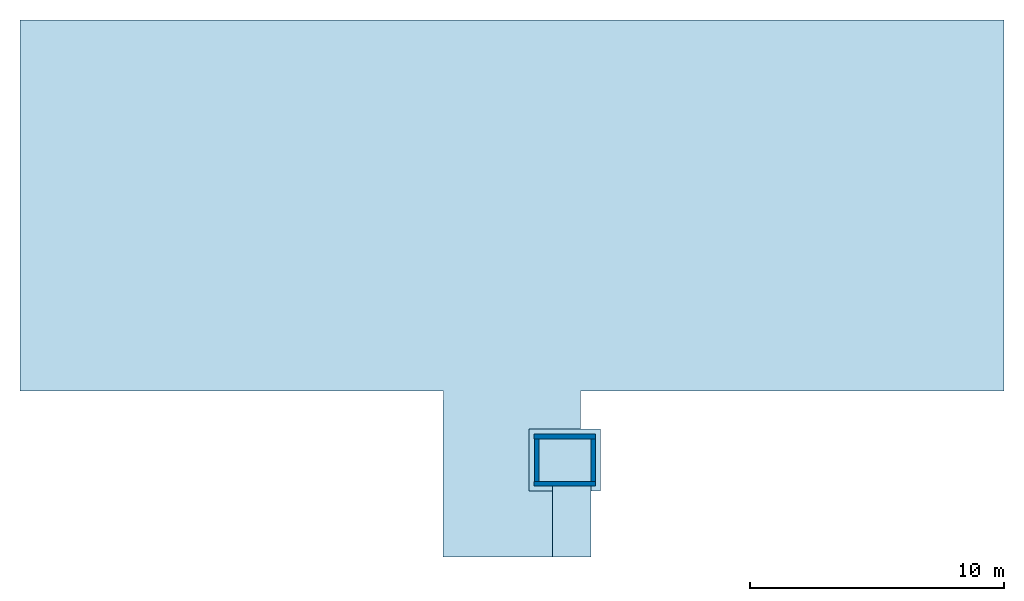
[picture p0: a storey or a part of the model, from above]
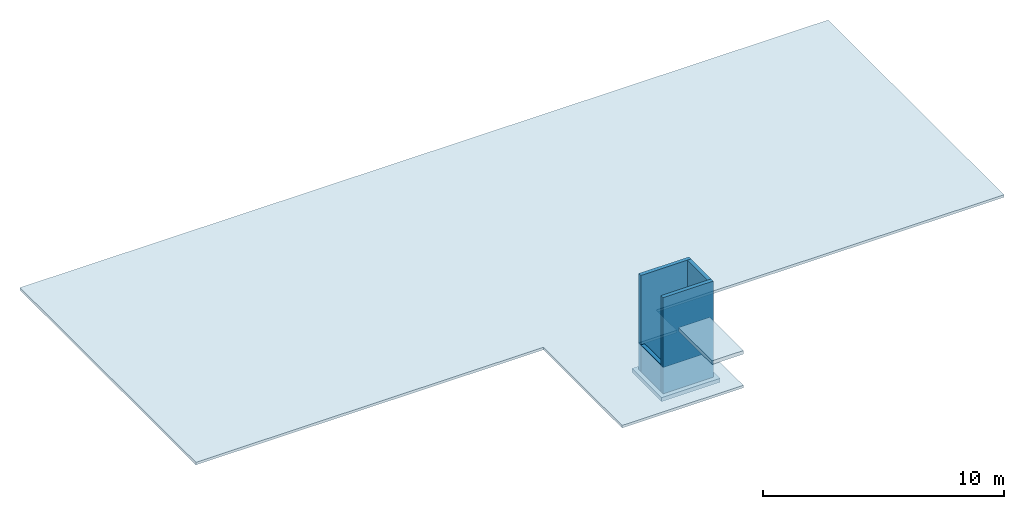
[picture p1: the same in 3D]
Properties of the parts of a building model (IFC2X3)

# File
Description: ViewDefinition [CoordinationView, QuantityTakeOffAddOnView]
File name: Numéro du projet
Time: 2018-01-29T14:30:11
Written by: The EXPRESS Data Manager Version 5.02.0100.07 : 28 Aug 2013
Made in: 20150714_1515(x64) - Exporter 16.0.490.0 - Default UI
Comment: STEP Physical File produced by: The EXPRESS Data Manager Version 5.02.0100.07 : 28 Aug 2013 * Module: EDMstepFileFactory/EDMstandAlone * Creation date: Mon Jan 29 14:30:11 2018 * Host: PC-STEPHANE * Database: C:\Users\STPHAN~1\AppData\Local\Temp\{60ED1AA9-D44B-4950-AAB7-048C5F7BB6E4}\ifc * Database version: 5507 * Database creation date: Mon Jan 29 14:30:02 2018 * Schema: IFC2X3 * Model: DataRepository.ifc * Model creation date: Mon Jan 29 14:30:02 2018 * Header model: DataRepository.ifc_HeaderModel * Header model creation date: Mon Jan 29 14:30:02 2018 * EDMuser: sdai-user * EDMgroup: sdai-group * License ID and type: 5605 : Permanent license. Expiry date: * EDMstepFileFactory options: 020000

# IfcProject, Numéro du projet
LongName: INNOVA PARK; Phase: Etat du projet

# IfcSite, Default
RefLatitude: 48, 51, 57, 604064; RefLongitude: 2, 19, 58, 799800; RefElevation: 0 m
Autre - Adresse du projet: Entrer l'adresse ici; Catégorie: Informations sur le projet; Date de fin du projet: Date de fin; Etat du projet: Etat du projet; Nom du client: Propriétaire; Nom du projet: INNOVA PARK; Numéro de projet: Numéro du projet
Données d'identification - Nom de l'organisation: PROJET BAT2; Nom du bâtiment: BATIMENT 1

# IfcBuilding, BATIMENT 1
LongName: BATIMENT 1
Pset_BuildingCommon - NumberOfStoreys: 5
Autre - Catégorie: Informations sur le projet; Adresse du projet: Entrer l'adresse ici; Date de fin du projet: Date de fin; Etat du projet: Etat du projet; Nom du client: Propriétaire; Nom du projet: INNOVA PARK; Numéro de projet: Numéro du projet
Données d'identification - Nom de l'organisation: PROJET BAT2; Nom du bâtiment: BATIMENT 1

# IfcBuildingStorey (5)
In: BATIMENT 1
Autre - Catégorie: Niveaux; Famille: Niveau: Pointe 8 mm; Famille et type: Niveau: Pointe 8 mm; ID du type: Niveau: Pointe 8 mm; Type: Niveau: Pointe 8 mm; Nom de la famille: Niveau
Cotes - Hauteur de calcul: 0 m
Données d'identification - Structure: no; Etage de bâtiment: yes; Nom du type: Pointe 8 mm
Contraintes - Base de l'élévation: Point de base du projet
Graphismes - Couleur: 0; Epaisseur des lignes: 1; Motif des lignes: Centre; Symbole: M_Marqueur de niveau - Point triangulaire: M_Marqueur de niveau - Point triangulaire; Valeur par défaut du symbole à l'extrémité 1: no; Valeur par défaut du symbole à l'extrémité 2: yes
Name | LongName = Nom | Elevation (m) = Elévation (m)
Fondations | Fondations | -0.7
RdC | RdC | 0
Niveau 1 | Niveau 1 | 3.52
Niveau 2 | Niveau 2 | 7.04
Terrasse brut | Terrasse brut | 10.25

# IfcBeam: Béton - Poutre rectangulaire:BG 0.20 x 0.48 C25/30:421361 (4)
Material: AEC Béton, C25/30
BaseQuantities - GrossVolume: 0.354331 m3
Pset_BeamCommon - LoadBearing: yes; IsExternal: no; Slope: 0 deg; Reference: BG 0.20 x 0.48 C25/30; Span: 1.95 m
Autre - Catégorie: Ossature; Famille: Béton - Poutre rectangulaire: BG 0.20 x 0.48 C25/30; Famille et type: Béton - Poutre rectangulaire: BG 0.20 x 0.48 C25/30; ID du type: Béton - Poutre rectangulaire: BG 0.20 x 0.48 C25/30; Type: Béton - Poutre rectangulaire: BG 0.20 x 0.48 C25/30; Nom de la famille: Béton - Poutre rectangulaire
Contraintes - Décalage du niveau d'arrivée: 0 m; Décalage du niveau de départ: 0 m; Orientation: Normale; Rotation de la section: 0 deg
Cotes - Longueur: 1.95 m; Surface: 0.96 m2; Volume: 0.108 m3; b: 0.2 m; h: 0.48 m
Matériaux et finitions - Matériau structurel: AEC Béton, C25/30
Phase de construction - Phase de création: Nouvelle construction
Position géométrique - Etat de la jonction: Deux jonctions activées; Justification Y: Origine; Justification YZ: Uniforme; Justification Z: Haut; Valeur de décalage Y: 0 m; Valeur de décalage Z: 0 m
Structure - Activer le modèle analytique: yes; Enrobage d'armature - Autres faces: Paramètres de l'enrobage d'armature: Enrobage d'armature 1; Enrobage d'armature - Face inférieure: Paramètres de l'enrobage d'armature: Enrobage d'armature 1; Utilisation structurelle: Longeron; Type d'attachement de début: Elévation d'arrivée; Longueur de coupe: 1.8 m; Forme de coupe: 0
Données d'identification - Nom du type: BG 0.20 x 0.48 C25/30; Numéro OmniClass: 23.25.30.11.14.14; Titre OmniClass: Beams
Name (Béton - Poutre rectangulaire:BG 0.20 x 0.48 C25/30:...) | In | Niveau de référence | Elévation du niveau de référence (m) = Elévation en haut (m) | Plan de construction | Elévation à la base (m)
421407 | Niveau 1 | Niveau: Niveau 1 | 3.52 | Niveau : Niveau 1 | 3.04
421436 | Niveau 1 | Niveau: Niveau 1 | 3.52 | Niveau : Niveau 1 | 3.04
442345 | Niveau 2 | Niveau: Niveau 2 | 7.04 | Niveau : Niveau 2 | 6.56
442348 | Niveau 2 | Niveau: Niveau 2 | 7.04 | Niveau : Niveau 2 | 6.56

# IfcBeam: Béton - Poutre rectangulaire:BG 0.25 x 0.43 C25/30:420141 (6)
In: Niveau 1
Material: AEC Béton, C25/30
Pset_BeamCommon - LoadBearing: yes; IsExternal: no; Slope: 0 deg; Reference: BG 0.25 x 0.43 C25/30
Autre - Catégorie: Ossature; Famille: Béton - Poutre rectangulaire: BG 0.25 x 0.43 C25/30; Famille et type: Béton - Poutre rectangulaire: BG 0.25 x 0.43 C25/30; ID du type: Béton - Poutre rectangulaire: BG 0.25 x 0.43 C25/30; Type: Béton - Poutre rectangulaire: BG 0.25 x 0.43 C25/30; Nom de la famille: Béton - Poutre rectangulaire
Contraintes - Décalage du niveau d'arrivée: 0 m; Décalage du niveau de départ: 0 m; Elévation du niveau de référence: 3.52 m; Niveau de référence: Niveau: Niveau 1; Orientation: Normale; Plan de construction: Niveau : Niveau 1; Rotation de la section: 0 deg
Cotes - Elévation à la base: 3.09 m; Elévation en haut: 3.52 m; b: 0.25 m; h: 0.43 m
Matériaux et finitions - Matériau structurel: AEC Béton, C25/30
Phase de construction - Phase de création: Nouvelle construction
Position géométrique - Etat de la jonction: Deux jonctions activées; Justification Y: Origine; Justification YZ: Uniforme; Justification Z: Haut; Valeur de décalage Y: 0 m; Valeur de décalage Z: 0 m
Structure - Activer le modèle analytique: yes; Enrobage d'armature - Autres faces: Paramètres de l'enrobage d'armature: Enrobage d'armature 1; Enrobage d'armature - Face inférieure: Paramètres de l'enrobage d'armature: Enrobage d'armature 1; Utilisation structurelle: Longeron; Forme de coupe: 0
Données d'identification - Nom du type: BG 0.25 x 0.43 C25/30; Numéro OmniClass: 23.25.30.11.14.14; Titre OmniClass: Beams
Name (Béton - Poutre rectangulaire:BG 0.25 x 0.43 C25/30:...) | Length (m) | CrossSectionArea (m2) | OuterSurfaceArea (m2) | GrossVolume (m3) | Span (m) = Longueur (m) | Surface (m2) | Volume (m3) | Longueur de coupe (m)
420690 | 4.5 | 0.0625 | 4.625 | 2.87073 | 14.8 | 7.1875 | 0.875 | 14.6
420933 | 4.5 | 0.0625 | 4.625 | 2.87073 | 14.8 | 7.1875 | 0.875 | 14.6
420949 | 4.5 | 0.0625 | 4.625 | 2.87073 | 14.8 | 7.1875 | 0.875 | 14.6
420965 | 4.5 | 0.0625 | 4.625 | 2.87073 | 14.8 | 7.1875 | 0.875 | 14.6
421045 |  |  |  | 0.973999 | 5 | 2.4375 | 0.296875 | 4.75 | Structure - Type d'attachement de début: Elévation d'arrivée
421179 |  |  |  | 0.973999 | 5 | 2.4375 | 0.296875 | 4.75 | Structure - Type d'attachement de début: Elévation d'arrivée

# IfcBeam: Béton - Poutre rectangulaire:BG 0.25 x 0.65 C25/30:443021 (6)
In: Niveau 2
Material: AEC Béton, C25/30
Pset_BeamCommon - LoadBearing: yes; IsExternal: no; Slope: 0 deg; Reference: BG 0.25 x 0.65 C25/30
Autre - Catégorie: Ossature; Famille: Béton - Poutre rectangulaire: BG 0.25 x 0.65 C25/30; Famille et type: Béton - Poutre rectangulaire: BG 0.25 x 0.65 C25/30; ID du type: Béton - Poutre rectangulaire: BG 0.25 x 0.65 C25/30; Type: Béton - Poutre rectangulaire: BG 0.25 x 0.65 C25/30; Nom de la famille: Béton - Poutre rectangulaire
Contraintes - Décalage du niveau d'arrivée: 0 m; Décalage du niveau de départ: 0 m; Orientation: Normale; Rotation de la section: 0 deg; Elévation du niveau de référence: 7.04 m; Niveau de référence: Niveau: Niveau 2; Plan de construction: Niveau : Niveau 2
Cotes - Elévation à la base: 6.39 m; Elévation en haut: 7.04 m; b: 0.25 m; h: 0.65 m
Matériaux et finitions - Matériau structurel: AEC Béton, C25/30
Phase de construction - Phase de création: Nouvelle construction
Position géométrique - Etat de la jonction: Deux jonctions activées; Justification Y: Origine; Justification YZ: Uniforme; Justification Z: Haut; Valeur de décalage Y: 0 m; Valeur de décalage Z: 0 m
Structure - Activer le modèle analytique: yes; Enrobage d'armature - Autres faces: Paramètres de l'enrobage d'armature: Enrobage d'armature 1; Enrobage d'armature - Face inférieure: Paramètres de l'enrobage d'armature: Enrobage d'armature 1; Utilisation structurelle: Longeron; Forme de coupe: 0
Données d'identification - Nom du type: BG 0.25 x 0.65 C25/30; Numéro OmniClass: 23.25.30.11.14.14; Titre OmniClass: Beams
Name (Béton - Poutre rectangulaire:BG 0.25 x 0.65 C25/30:...) | Length (m) | CrossSectionArea (m2) | OuterSurfaceArea (m2) | GrossVolume (m3) | Span (m) = Longueur (m) | Surface (m2) | Volume (m3) | Longueur de coupe (m)
442332 | 4.5 | 0.1175 | 6.715 | 5.39698 | 14.8 | 10.4325 | 1.645 | 14.6
442334 | 4.5 | 0.1175 | 6.715 | 5.39698 | 14.8 | 10.4325 | 1.645 | 14.6
442336 | 4.5 | 0.1175 | 6.715 | 5.39698 | 14.8 | 10.4325 | 1.645 | 14.6
442338 | 4.5 | 0.1175 | 6.715 | 5.39698 | 14.8 | 10.4325 | 1.645 | 14.6
442340 |  |  |  | 1.83112 | 5 | 3.5375 | 0.558125 | 4.75 | Structure - Type d'attachement de début: Elévation d'arrivée
442342 |  |  |  | 1.83112 | 5 | 3.5375 | 0.558125 | 4.75 | Structure - Type d'attachement de début: Elévation d'arrivée

# IfcBeam: Béton - Poutre rectangulaire:BG PR 0.20 x 0.39 C25/30:443918 (3)
In: Niveau 2
Material: AEC Béton, C25/30
Pset_BeamCommon - LoadBearing: yes; IsExternal: no; Slope: 0 deg; Reference: BG PR 0.20 x 0.39 C25/30
Autre - Catégorie: Ossature; Famille: Béton - Poutre rectangulaire: BG PR 0.20 x 0.39 C25/30; Famille et type: Béton - Poutre rectangulaire: BG PR 0.20 x 0.39 C25/30; ID du type: Béton - Poutre rectangulaire: BG PR 0.20 x 0.39 C25/30; Type: Béton - Poutre rectangulaire: BG PR 0.20 x 0.39 C25/30; Nom de la famille: Béton - Poutre rectangulaire
Contraintes - Décalage du niveau d'arrivée: 0 m; Décalage du niveau de départ: 0 m; Orientation: Normale; Rotation de la section: 0 deg; Niveau de référence: Niveau: Niveau 2; Elévation du niveau de référence: 7.04 m; Plan de construction: Niveau : Niveau 2
Cotes - Elévation à la base: 6.86 m; Elévation en haut: 7.25 m; b: 0.2 m; h: 0.39 m
Matériaux et finitions - Matériau structurel: AEC Béton, C25/30
Phase de construction - Phase de création: Nouvelle construction
Position géométrique - Etat de la jonction: Deux jonctions activées; Justification Y: Origine; Justification YZ: Uniforme; Justification Z: Haut; Valeur de décalage Y: 0.21 m; Valeur de décalage Z: 0.21 m
Structure - Activer le modèle analytique: yes; Enrobage d'armature - Autres faces: Paramètres de l'enrobage d'armature: Enrobage d'armature 1; Utilisation structurelle: Longeron; Forme de coupe: 0
Données d'identification - Nom du type: BG PR 0.20 x 0.39 C25/30; Numéro OmniClass: 23.25.30.11.14.14; Titre OmniClass: Beams
Name (Béton - Poutre rectangulaire:BG PR 0.20 x 0.39 C25/30:...) | GrossVolume (m3) | Span (m) = Longueur (m) | Surface (m2) | Volume (m3) | Longueur de coupe (m)
444093 | 5.33547 | 38.92 | 15.9385 | 1.62625 | 38.9205 | Structure - Enrobage d'armature - Face inférieure: Paramètres de l'enrobage d'armature: Enrobage d'armature 1
444232 | 2.26949 | 16.66 | 6.8178 | 0.69174 | 16.66 | Structure - Enrobage d'armature - Face supérieure: Paramètres de l'enrobage d'armature: Enrobage d'armature 1
445462 | 2.26811 | 16.66 | 6.81171 | 0.69132 | 16.66

# IfcColumn: BG 0.25 x 0.30 C25/30 (20)
Type - ElementType: BG 0.25 x 0.30 C25/30; PredefinedType: COLUMN; Material: AEC Béton, C25/30
Type - Autre - Catégorie: Poteaux porteurs; Nom de la famille: Béton - Rectangulaire - Poteau
Type - Cotes - b: 0.25 m; h: 0.3 m
Type - Données d'identification - Nom du type: BG 0.25 x 0.30 C25/30
Type - Structure - Forme de coupe: 0
BaseQuantities - Length: 3.34 m; CrossSectionArea: 0.075 m2; OuterSurfaceArea: 3.824 m2
Pset_ColumnCommon - LoadBearing: yes; Reference: BG 0.25 x 0.30 C25/30; IsExternal: no; Slope: 0 deg
Autre - Famille: Béton - Rectangulaire - Poteau: BG 0.25 x 0.30 C25/30; Famille et type: Béton - Rectangulaire - Poteau: BG 0.25 x 0.30 C25/30; ID du type: Béton - Rectangulaire - Poteau: BG 0.25 x 0.30 C25/30; Type: Béton - Rectangulaire - Poteau: BG 0.25 x 0.30 C25/30
Contraintes - Décalage inférieur: 0 m; Décalage supérieur: 0 m; Limite de pièce: yes; Se déplace avec les quadrillages: yes; Style de poteau: Vertical
Matériaux et finitions - Matériau structurel: AEC Béton, C25/30
Phase de construction - Phase de création: Nouvelle construction
Structure - Activer le modèle analytique: yes; Enrobage d'armature - Autres faces: Paramètres de l'enrobage d'armature: Enrobage d'armature 1
Name (Béton - Rectangulaire - Poteau:BG 0.25 x 0.30 C25/30:...) | In | GrossVolume (m3) | Marque d'emplacement du poteau | Niveau = Niveau de base | Niveau supérieur | Longueur (m) | Surface (m2) | Volume (m3)
415848 | Fondations | 0.962106 | B-2 | Niveau: Fondations | Niveau: Niveau 1 | 4.22 | 2.3005 | 0.29325 | Données d'identification - Identifiant: P1; Structure - Enrobage d'armature - Face inférieure: Paramètres de l'enrobage d'armature: Enrobage d'armature 1
416358 | Fondations | 0.962106 | B-3 | Niveau: Fondations | Niveau: Niveau 1 | 4.22 | 2.3005 | 0.29325 | Données d'identification - Identifiant: P2; Structure - Enrobage d'armature - Face inférieure: Paramètres de l'enrobage d'armature: Enrobage d'armature 1
416373 | Fondations | 0.962106 | B-4 | Niveau: Fondations | Niveau: Niveau 1 | 4.22 | 2.3005 | 0.29325 | Structure - Enrobage d'armature - Face inférieure: Paramètres de l'enrobage d'armature: Enrobage d'armature 1
416392 | Fondations | 0.962106 | B-6 | Niveau: Fondations | Niveau: Niveau 1 | 4.22 | 2.3005 | 0.29325 | Structure - Enrobage d'armature - Face inférieure: Paramètres de l'enrobage d'armature: Enrobage d'armature 1
416411 | Fondations | 0.962106 | B-9 | Niveau: Fondations | Niveau: Niveau 1 | 4.22 | 2.3005 | 0.29325 | Structure - Enrobage d'armature - Face inférieure: Paramètres de l'enrobage d'armature: Enrobage d'armature 1
416426 | Fondations | 0.962106 | B-10 | Niveau: Fondations | Niveau: Niveau 1 | 4.22 | 2.3005 | 0.29325 | Structure - Enrobage d'armature - Face inférieure: Paramètres de l'enrobage d'armature: Enrobage d'armature 1
416505 | Fondations | 0.962106 | D-2 | Niveau: Fondations | Niveau: Niveau 1 | 4.22 | 2.3005 | 0.29325 | Structure - Enrobage d'armature - Face inférieure: Paramètres de l'enrobage d'armature: Enrobage d'armature 1
416520 | Fondations | 0.962106 | D-3 | Niveau: Fondations | Niveau: Niveau 1 | 4.22 | 2.3005 | 0.29325 | Structure - Enrobage d'armature - Face inférieure: Paramètres de l'enrobage d'armature: Enrobage d'armature 1
416537 | Fondations | 0.962106 | D-9 | Niveau: Fondations | Niveau: Niveau 1 | 4.22 | 2.3005 | 0.29325 | Structure - Enrobage d'armature - Face inférieure: Paramètres de l'enrobage d'armature: Enrobage d'armature 1
416554 | Fondations | 0.962106 | D-10 | Niveau: Fondations | Niveau: Niveau 1 | 4.22 | 2.3005 | 0.29325 | Structure - Enrobage d'armature - Face inférieure: Paramètres de l'enrobage d'armature: Enrobage d'armature 1
442285 | Niveau 1 | 0.82185 | B-2 | Niveau: Niveau 1 | Niveau: Niveau 2 | 3.52 | 1.912 | 0.2505
442287 | Niveau 1 | 0.82185 | B-3 | Niveau: Niveau 1 | Niveau: Niveau 2 | 3.52 | 1.912 | 0.2505
442289 | Niveau 1 | 0.82185 | B-4 | Niveau: Niveau 1 | Niveau: Niveau 2 | 3.52 | 1.912 | 0.2505
442291 | Niveau 1 | 0.82185 | B-6 | Niveau: Niveau 1 | Niveau: Niveau 2 | 3.52 | 1.912 | 0.2505
442293 | Niveau 1 | 0.82185 | B-9 | Niveau: Niveau 1 | Niveau: Niveau 2 | 3.52 | 1.912 | 0.2505
442295 | Niveau 1 | 0.82185 | B-10 | Niveau: Niveau 1 | Niveau: Niveau 2 | 3.52 | 1.912 | 0.2505
442297 | Niveau 1 | 0.82185 | D-2 | Niveau: Niveau 1 | Niveau: Niveau 2 | 3.52 | 1.912 | 0.2505
442299 | Niveau 1 | 0.82185 | D-3 | Niveau: Niveau 1 | Niveau: Niveau 2 | 3.52 | 1.912 | 0.2505
442301 | Niveau 1 | 0.82185 | D-9 | Niveau: Niveau 1 | Niveau: Niveau 2 | 3.52 | 1.912 | 0.2505
442303 | Niveau 1 | 0.82185 | D-10 | Niveau: Niveau 1 | Niveau: Niveau 2 | 3.52 | 1.912 | 0.2505

# IfcOpeningElement: Opening (93)
BaseQuantities - Depth: 0.2 m
Name | In | Height (m) | Width (m) | Catégorie | Décalage supérieur (m) | Contrainte inférieure | Décalage inférieur (m) | Hauteur non contrainte (m) | Phase de création
14 x Mur de base:BG VOILE BA 0.20 C25/30:410724 | Fondations | 0.92 | 2.1 | Ouverture de mur rectiligne rectangulaire | 0 | Niveau: RdC | 0.1 | 2.1 | Nouvelle construction
5 x Mur de base:BG VOILE BA 0.20 C25/30:416854 | Fondations | 0.92 | 2.1 | Ouverture de mur rectiligne rectangulaire | 0 | Niveau: RdC | 0.1 | 2.1 | Nouvelle construction
Mur de base:BG VOILE BA 0.20 C25/30:416854 | Fondations | 1.07 | 2.16 | Ouverture de mur rectiligne rectangulaire | 0 | Niveau: RdC | 0 | 2.16 | Nouvelle construction
Mur de base:BG VOILE BA 0.20 C25/30:417377 | Fondations | 1.14 | 2.2 | Ouverture de mur rectiligne rectangulaire | 0 | Niveau: RdC | 0.15 | 2.2 | Nouvelle construction
2 x Mur de base:BG VOILE BA 0.20 C25/30:417377 | Fondations | 1.01 | 1.2 | Ouverture de mur rectiligne rectangulaire | 0 | Niveau: RdC | 1 | 1.2 | Nouvelle construction
6 x Mur de base:BG VOILE BA 0.20 C25/30:417552 | Fondations | 0.92 | 2.1 | Ouverture de mur rectiligne rectangulaire | 0 | Niveau: RdC | 0.1 | 2.1 | Nouvelle construction
Mur de base:BG VOILE BA 0.20 C25/30:418211 | Fondations | 1.14 | 2.2 | Ouverture de mur rectiligne rectangulaire | 0 | Niveau: RdC | 0.15 | 2.2 | Nouvelle construction
2 x Mur de base:BG VOILE BA 0.20 C25/30:418211 | Fondations | 1.01 | 1.2 | Ouverture de mur rectiligne rectangulaire | 0 | Niveau: RdC | 1 | 1.2 | Nouvelle construction
14 x Mur de base:BG VOILE BA 0.20 C25/30:442282 | Niveau 1 | 0.92 | 2.08 | Ouverture de mur rectiligne rectangulaire | 0 | Niveau: Niveau 1 | 0.12 | 2.08 | Nouvelle construction
6 x Mur de base:BG VOILE BA 0.20 C25/30:442309 | Niveau 1 | 0.92 | 2.08 | Ouverture de mur rectiligne rectangulaire | 0 | Niveau: Niveau 1 | 0.12 | 2.08 | Nouvelle construction
Mur de base:BG VOILE BA 0.20 C25/30:442313 | Niveau 1 | 1.05 | 2.2 | Ouverture de mur rectiligne rectangulaire | 0 | Niveau: Niveau 1 | 0 | 2.2 | Nouvelle construction
2 x Mur de base:BG VOILE BA 0.20 C25/30:442313 | Niveau 1 | 0.92 | 1.2 | Ouverture de mur rectiligne rectangulaire | 0 | Niveau: Niveau 1 | 1 | 1.2 | Nouvelle construction
6 x Mur de base:BG VOILE BA 0.20 C25/30:442315 | Niveau 1 | 0.92 | 2.08 | Ouverture de mur rectiligne rectangulaire | 0 | Niveau: Niveau 1 | 0.12 | 2.08 | Nouvelle construction
Mur de base:BG VOILE BA 0.20 C25/30:442319 | Niveau 1 | 1.05 | 2.2 | Ouverture de mur rectiligne rectangulaire | 0 | Niveau: Niveau 1 | 0 | 2.2 | Nouvelle construction
2 x Mur de base:BG VOILE BA 0.20 C25/30:442319 | Niveau 1 | 0.92 | 1.2 | Ouverture de mur rectiligne rectangulaire | 0 | Niveau: Niveau 1 | 1 | 1.2 | Nouvelle construction
14 x Mur de base:BG VOILE BA 0.20 C25/30:447258 | Niveau 2 | 0.92 | 2.1 | Ouverture de mur rectiligne rectangulaire | 0 | Niveau: Niveau 2 | 0.3 | 2.1 | Nouvelle construction
Mur de base:BG VOILE BA 0.20 C25/30:448893 | Niveau 2 | 1.05 | 2.2 | Ouverture de mur rectiligne rectangulaire | 0 | Niveau: Niveau 2 | 0 | 2.2 | Nouvelle construction
Mur de base:BG VOILE BA 0.20 C25/30:449741 | Niveau 2 | 1.05 | 2.2 | Ouverture de mur rectiligne rectangulaire | 0 | Niveau: Niveau 2 | 0 | 2.2 | Nouvelle construction
6 x Mur de base:BG VOILE BA 0.20 C25/30:449856 | Niveau 2 | 0.92 | 2.1 | Ouverture de mur rectiligne rectangulaire | 0 | Niveau: Niveau 2 | 0.3 | 2.1 | Nouvelle construction
6 x Mur de base:BG VOILE BA 0.20 C25/30:450434 | Niveau 2 | 0.92 | 2.1 | Ouverture de mur rectiligne rectangulaire | -0.81 | Niveau: Niveau 2 | 0.3 | 2.1 | Nouvelle construction | Contraintes - Contrainte supérieure: Niveau: Terrasse brut
 | Terrasse brut | 2.02 | 1.02

# IfcSlab: M_Base-Rectangulaire:BG SI 0.80 x 0.80 x 0.25 C25/30, M_Base-Rectangulaire:BG SI 0.80 x 0.80 x 0.25 C25/30:431764
In: Fondations
PredefinedType: FLOOR; Material: AEC Béton, C25/30
Pset_SlabCommon - LoadBearing: yes; IsExternal: no; Reference: BG SI 0.80 x 0.80 x 0.25 C25/30
Autre - Catégorie: Fondations; Famille: M_Base-Rectangulaire: BG SI 0.80 x 0.80 x 0.25 C25/30; Famille et type: M_Base-Rectangulaire: BG SI 0.80 x 0.80 x 0.25 C25/30; ID du type: M_Base-Rectangulaire: BG SI 0.80 x 0.80 x 0.25 C25/30; Type: M_Base-Rectangulaire: BG SI 0.80 x 0.80 x 0.25 C25/30; Nom de la famille: M_Base-Rectangulaire
Contraintes - Niveau: Niveau: Fondations; Se déplace avec les quadrillages: yes; Décalage: 0 m; Hôte: Niveau : Fondations
Cotes - Elévation à la base: -0.95 m; Elévation en haut: -0.7 m; Largeur: 0.8 m; Longueur: 0.8 m; Surface: 0.64 m2; Volume: 0.16 m3; Epaisseur: 0.25 m
Matériaux et finitions - Matériau structurel: AEC Béton, C25/30
Phase de construction - Phase de création: Nouvelle construction
Structure - Activer le modèle analytique: yes; Enrobage d'armature - Autres faces: Paramètres de l'enrobage d'armature: Enrobage d'armature 1; Enrobage d'armature - Face inférieure: Paramètres de l'enrobage d'armature: Enrobage d'armature 1; Enrobage d'armature - Face supérieure: Paramètres de l'enrobage d'armature: Enrobage d'armature 1
Données d'identification - Nom du type: BG SI 0.80 x 0.80 x 0.25 C25/30

# IfcSlab: M_Base-Rectangulaire:BG SI 1.00 x 1.00 x 0.25 C25/30, M_Base-Rectangulaire:BG SI 1.00 x 1.00 x 0.25 C25/30:432122
In: Fondations
PredefinedType: FLOOR; Material: AEC Béton, C25/30
Pset_SlabCommon - LoadBearing: yes; IsExternal: no; Reference: BG SI 1.00 x 1.00 x 0.25 C25/30
Autre - Catégorie: Fondations; Famille: M_Base-Rectangulaire: BG SI 1.00 x 1.00 x 0.25 C25/30; Famille et type: M_Base-Rectangulaire: BG SI 1.00 x 1.00 x 0.25 C25/30; ID du type: M_Base-Rectangulaire: BG SI 1.00 x 1.00 x 0.25 C25/30; Type: M_Base-Rectangulaire: BG SI 1.00 x 1.00 x 0.25 C25/30; Nom de la famille: M_Base-Rectangulaire
Contraintes - Se déplace avec les quadrillages: yes; Décalage: 0 m; Niveau: Niveau: Fondations; Hôte: Niveau : Fondations
Cotes - Elévation à la base: -0.95 m; Elévation en haut: -0.7 m; Largeur: 1 m; Longueur: 1 m; Surface: 1 m2; Volume: 0.25 m3; Epaisseur: 0.25 m
Matériaux et finitions - Matériau structurel: AEC Béton, C25/30
Phase de construction - Phase de création: Nouvelle construction
Structure - Activer le modèle analytique: yes; Enrobage d'armature - Autres faces: Paramètres de l'enrobage d'armature: Enrobage d'armature 1; Enrobage d'armature - Face inférieure: Paramètres de l'enrobage d'armature: Enrobage d'armature 1; Enrobage d'armature - Face supérieure: Paramètres de l'enrobage d'armature: Enrobage d'armature 1
Données d'identification - Nom du type: BG SI 1.00 x 1.00 x 0.25 C25/30

# IfcSlab: M_Base-Rectangulaire:BG SI 1.10 x 1.10 x 0.30 C25/30 (3)
In: Fondations
PredefinedType: FLOOR; Material: AEC Béton, C25/30
Pset_SlabCommon - LoadBearing: yes; IsExternal: no; Reference: BG SI 1.10 x 1.10 x 0.30 C25/30
Autre - Catégorie: Fondations; Famille: M_Base-Rectangulaire: BG SI 1.10 x 1.10 x 0.30 C25/30; Famille et type: M_Base-Rectangulaire: BG SI 1.10 x 1.10 x 0.30 C25/30; ID du type: M_Base-Rectangulaire: BG SI 1.10 x 1.10 x 0.30 C25/30; Type: M_Base-Rectangulaire: BG SI 1.10 x 1.10 x 0.30 C25/30; Nom de la famille: M_Base-Rectangulaire
Contraintes - Niveau: Niveau: Fondations; Se déplace avec les quadrillages: yes; Décalage: 0 m; Hôte: Niveau : Fondations
Cotes - Elévation à la base: -1 m; Elévation en haut: -0.7 m; Largeur: 1.1 m; Longueur: 1.1 m; Surface: 1.21 m2; Volume: 0.363 m3; Epaisseur: 0.3 m
Matériaux et finitions - Matériau structurel: AEC Béton, C25/30
Phase de construction - Phase de création: Nouvelle construction
Structure - Activer le modèle analytique: yes; Enrobage d'armature - Autres faces: Paramètres de l'enrobage d'armature: Enrobage d'armature 1; Enrobage d'armature - Face inférieure: Paramètres de l'enrobage d'armature: Enrobage d'armature 1; Enrobage d'armature - Face supérieure: Paramètres de l'enrobage d'armature: Enrobage d'armature 1
Données d'identification - Nom du type: BG SI 1.10 x 1.10 x 0.30 C25/30
Name (M_Base-Rectangulaire:BG SI 1.10 x 1.10 x 0.30 C25/30:...)
433193
433422
433663

# IfcSlab: M_Base-Rectangulaire:BG SI 1.20x 2.40 x 0.35 C25/30 (2)
In: Fondations
PredefinedType: FLOOR; Material: AEC Béton, C25/30
Pset_SlabCommon - LoadBearing: yes; IsExternal: no; Reference: BG SI 1.20x 2.40 x 0.35 C25/30
Autre - Catégorie: Fondations; Famille: M_Base-Rectangulaire: BG SI 1.20x 2.40 x 0.35 C25/30; Famille et type: M_Base-Rectangulaire: BG SI 1.20x 2.40 x 0.35 C25/30; ID du type: M_Base-Rectangulaire: BG SI 1.20x 2.40 x 0.35 C25/30; Type: M_Base-Rectangulaire: BG SI 1.20x 2.40 x 0.35 C25/30; Nom de la famille: M_Base-Rectangulaire
Contraintes - Niveau: Niveau: Fondations; Se déplace avec les quadrillages: yes; Décalage: 0 m; Hôte: Niveau : Fondations
Cotes - Elévation à la base: -1.05 m; Elévation en haut: -0.7 m; Largeur: 1.2 m; Longueur: 2.4 m; Surface: 2.88 m2; Volume: 1.008 m3; Epaisseur: 0.35 m
Matériaux et finitions - Matériau structurel: AEC Béton, C25/30
Phase de construction - Phase de création: Nouvelle construction
Structure - Activer le modèle analytique: yes; Enrobage d'armature - Autres faces: Paramètres de l'enrobage d'armature: Enrobage d'armature 1; Enrobage d'armature - Face inférieure: Paramètres de l'enrobage d'armature: Enrobage d'armature 1; Enrobage d'armature - Face supérieure: Paramètres de l'enrobage d'armature: Enrobage d'armature 1
Données d'identification - Nom du type: BG SI 1.20x 2.40 x 0.35 C25/30
Name (M_Base-Rectangulaire:BG SI 1.20x 2.40 x 0.35 C25/30:...)
431236
431718

# IfcSlab: M_Base-Rectangulaire:BG SI 1.30 x 1.30 x 0.35 C25/30, M_Base-Rectangulaire:BG SI 1.30 x 1.30 x 0.35 C25/30:432809
In: Fondations
PredefinedType: FLOOR; Material: AEC Béton, C25/30
Pset_SlabCommon - LoadBearing: yes; IsExternal: no; Reference: BG SI 1.30 x 1.30 x 0.35 C25/30
Autre - Catégorie: Fondations; Famille: M_Base-Rectangulaire: BG SI 1.30 x 1.30 x 0.35 C25/30; Famille et type: M_Base-Rectangulaire: BG SI 1.30 x 1.30 x 0.35 C25/30; ID du type: M_Base-Rectangulaire: BG SI 1.30 x 1.30 x 0.35 C25/30; Type: M_Base-Rectangulaire: BG SI 1.30 x 1.30 x 0.35 C25/30; Nom de la famille: M_Base-Rectangulaire
Contraintes - Niveau: Niveau: Fondations; Se déplace avec les quadrillages: yes; Décalage: 0 m; Hôte: Niveau : Fondations
Cotes - Elévation à la base: -1.05 m; Elévation en haut: -0.7 m; Largeur: 1.3 m; Longueur: 1.3 m; Surface: 1.69 m2; Volume: 0.5915 m3; Epaisseur: 0.35 m
Matériaux et finitions - Matériau structurel: AEC Béton, C25/30
Phase de construction - Phase de création: Nouvelle construction
Structure - Activer le modèle analytique: yes; Enrobage d'armature - Autres faces: Paramètres de l'enrobage d'armature: Enrobage d'armature 1; Enrobage d'armature - Face inférieure: Paramètres de l'enrobage d'armature: Enrobage d'armature 1; Enrobage d'armature - Face supérieure: Paramètres de l'enrobage d'armature: Enrobage d'armature 1
Données d'identification - Nom du type: BG SI 1.30 x 1.30 x 0.35 C25/30

# IfcSlab: M_Base-Rectangulaire:BG SI 1.40 x 1.40 x 0.35 C25/30 (6)
In: Fondations
PredefinedType: FLOOR; Material: AEC Béton, C25/30
Pset_SlabCommon - LoadBearing: yes; IsExternal: no; Reference: BG SI 1.40 x 1.40 x 0.35 C25/30
Autre - Catégorie: Fondations; Famille: M_Base-Rectangulaire: BG SI 1.40 x 1.40 x 0.35 C25/30; Famille et type: M_Base-Rectangulaire: BG SI 1.40 x 1.40 x 0.35 C25/30; ID du type: M_Base-Rectangulaire: BG SI 1.40 x 1.40 x 0.35 C25/30; Type: M_Base-Rectangulaire: BG SI 1.40 x 1.40 x 0.35 C25/30; Nom de la famille: M_Base-Rectangulaire
Contraintes - Niveau: Niveau: Fondations; Se déplace avec les quadrillages: yes; Décalage: 0 m; Hôte: Niveau : Fondations
Cotes - Elévation à la base: -1.05 m; Elévation en haut: -0.7 m; Largeur: 1.4 m; Longueur: 1.4 m; Surface: 1.96 m2; Volume: 0.686 m3; Epaisseur: 0.35 m
Matériaux et finitions - Matériau structurel: AEC Béton, C25/30
Phase de construction - Phase de création: Nouvelle construction
Structure - Activer le modèle analytique: yes; Enrobage d'armature - Autres faces: Paramètres de l'enrobage d'armature: Enrobage d'armature 1; Enrobage d'armature - Face inférieure: Paramètres de l'enrobage d'armature: Enrobage d'armature 1; Enrobage d'armature - Face supérieure: Paramètres de l'enrobage d'armature: Enrobage d'armature 1
Données d'identification - Nom du type: BG SI 1.40 x 1.40 x 0.35 C25/30
Name (M_Base-Rectangulaire:BG SI 1.40 x 1.40 x 0.35 C25/30:...)
427728 | Données d'identification - Identifiant: S5
427982
427991
427998
430670
430679

# IfcSlab: M_Base-Rectangulaire:BG SI 1.50x 1.50 x 0.40 C25/30 (3)
In: Fondations
PredefinedType: FLOOR; Material: AEC Béton, C25/30
Pset_SlabCommon - LoadBearing: yes; IsExternal: no; Reference: BG SI 1.50x 1.50 x 0.40 C25/30
Autre - Catégorie: Fondations; Famille: M_Base-Rectangulaire: BG SI 1.50x 1.50 x 0.40 C25/30; Famille et type: M_Base-Rectangulaire: BG SI 1.50x 1.50 x 0.40 C25/30; ID du type: M_Base-Rectangulaire: BG SI 1.50x 1.50 x 0.40 C25/30; Type: M_Base-Rectangulaire: BG SI 1.50x 1.50 x 0.40 C25/30; Nom de la famille: M_Base-Rectangulaire
Contraintes - Se déplace avec les quadrillages: yes; Décalage: 0 m; Niveau: Niveau: Fondations; Hôte: Niveau : Fondations
Cotes - Elévation à la base: -1.1 m; Elévation en haut: -0.7 m; Largeur: 1.5 m; Longueur: 1.5 m; Surface: 2.25 m2; Volume: 0.9 m3; Epaisseur: 0.4 m
Matériaux et finitions - Matériau structurel: AEC Béton, C25/30
Phase de construction - Phase de création: Nouvelle construction
Structure - Activer le modèle analytique: yes; Enrobage d'armature - Autres faces: Paramètres de l'enrobage d'armature: Enrobage d'armature 1; Enrobage d'armature - Face inférieure: Paramètres de l'enrobage d'armature: Enrobage d'armature 1; Enrobage d'armature - Face supérieure: Paramètres de l'enrobage d'armature: Enrobage d'armature 1
Données d'identification - Nom du type: BG SI 1.50x 1.50 x 0.40 C25/30
Name (M_Base-Rectangulaire:BG SI 1.50x 1.50 x 0.40 C25/30:...)
430786
430795
432445

# IfcSlab: M_Base-Rectangulaire:BG SI 1.70 x 1.70 x 0.45 C25/30 (18)
In: Fondations
PredefinedType: FLOOR; Material: AEC Béton, C25/30
Pset_SlabCommon - LoadBearing: yes; IsExternal: no; Reference: BG SI 1.70 x 1.70 x 0.45 C25/30
Autre - Catégorie: Fondations; Famille: M_Base-Rectangulaire: BG SI 1.70 x 1.70 x 0.45 C25/30; Famille et type: M_Base-Rectangulaire: BG SI 1.70 x 1.70 x 0.45 C25/30; ID du type: M_Base-Rectangulaire: BG SI 1.70 x 1.70 x 0.45 C25/30; Type: M_Base-Rectangulaire: BG SI 1.70 x 1.70 x 0.45 C25/30; Nom de la famille: M_Base-Rectangulaire
Contraintes - Se déplace avec les quadrillages: yes; Décalage: 0 m; Niveau: Niveau: Fondations; Hôte: Niveau : Fondations
Cotes - Elévation à la base: -1.15 m; Elévation en haut: -0.7 m; Largeur: 1.7 m; Longueur: 1.7 m; Surface: 2.89 m2; Volume: 1.3005 m3; Epaisseur: 0.45 m
Matériaux et finitions - Matériau structurel: AEC Béton, C25/30
Phase de construction - Phase de création: Nouvelle construction
Structure - Activer le modèle analytique: yes; Enrobage d'armature - Autres faces: Paramètres de l'enrobage d'armature: Enrobage d'armature 1; Enrobage d'armature - Face inférieure: Paramètres de l'enrobage d'armature: Enrobage d'armature 1; Enrobage d'armature - Face supérieure: Paramètres de l'enrobage d'armature: Enrobage d'armature 1
Données d'identification - Nom du type: BG SI 1.70 x 1.70 x 0.45 C25/30
Name (M_Base-Rectangulaire:BG SI 1.70 x 1.70 x 0.45 C25/30:...)
428045
428682
428691
428706
428715
428724
428818
428997
429438
429589
429854
429863
429876
429883
429953
429955
429957
429959

# IfcSlab: M_Base-Rectangulaire:BG SI 1.80 x 1.80 x 0.45 C25/30, M_Base-Rectangulaire:BG SI 1.80 x 1.80 x 0.45 C25/30:432512
In: Fondations
PredefinedType: FLOOR; Material: AEC Béton, C25/30
Pset_SlabCommon - LoadBearing: yes; IsExternal: no; Reference: BG SI 1.80 x 1.80 x 0.45 C25/30
Autre - Catégorie: Fondations; Famille: M_Base-Rectangulaire: BG SI 1.80 x 1.80 x 0.45 C25/30; Famille et type: M_Base-Rectangulaire: BG SI 1.80 x 1.80 x 0.45 C25/30; ID du type: M_Base-Rectangulaire: BG SI 1.80 x 1.80 x 0.45 C25/30; Type: M_Base-Rectangulaire: BG SI 1.80 x 1.80 x 0.45 C25/30; Nom de la famille: M_Base-Rectangulaire
Contraintes - Niveau: Niveau: Fondations; Se déplace avec les quadrillages: yes; Décalage: 0 m; Hôte: Niveau : Fondations
Cotes - Elévation à la base: -1.15 m; Elévation en haut: -0.7 m; Largeur: 1.8 m; Longueur: 1.8 m; Surface: 3.24 m2; Volume: 1.458 m3; Epaisseur: 0.45 m
Matériaux et finitions - Matériau structurel: AEC Béton, C25/30
Phase de construction - Phase de création: Nouvelle construction
Structure - Activer le modèle analytique: yes; Enrobage d'armature - Autres faces: Paramètres de l'enrobage d'armature: Enrobage d'armature 1; Enrobage d'armature - Face inférieure: Paramètres de l'enrobage d'armature: Enrobage d'armature 1; Enrobage d'armature - Face supérieure: Paramètres de l'enrobage d'armature: Enrobage d'armature 1
Données d'identification - Nom du type: BG SI 1.80 x 1.80 x 0.45 C25/30

# IfcSlab: M_Base-Rectangulaire:BG SI 1.90x 0.50 x 0.25 C25/30, M_Base-Rectangulaire:BG SI 1.90x 0.50 x 0.25 C25/30:433990
In: Fondations
PredefinedType: FLOOR; Material: AEC Béton, C25/30
Pset_SlabCommon - LoadBearing: yes; IsExternal: no; Reference: BG SI 1.90x 0.50 x 0.25 C25/30
Autre - Catégorie: Fondations; Famille: M_Base-Rectangulaire: BG SI 1.90x 0.50 x 0.25 C25/30; Famille et type: M_Base-Rectangulaire: BG SI 1.90x 0.50 x 0.25 C25/30; ID du type: M_Base-Rectangulaire: BG SI 1.90x 0.50 x 0.25 C25/30; Type: M_Base-Rectangulaire: BG SI 1.90x 0.50 x 0.25 C25/30; Nom de la famille: M_Base-Rectangulaire
Contraintes - Se déplace avec les quadrillages: yes; Décalage: 0 m; Niveau: Niveau: Fondations; Hôte: Niveau : Fondations
Cotes - Elévation à la base: -0.95 m; Elévation en haut: -0.7 m; Largeur: 1.9 m; Longueur: 0.5 m; Surface: 0.95 m2; Volume: 0.2375 m3; Epaisseur: 0.25 m
Matériaux et finitions - Matériau structurel: AEC Béton, C25/30
Phase de construction - Phase de création: Nouvelle construction
Structure - Activer le modèle analytique: yes; Enrobage d'armature - Autres faces: Paramètres de l'enrobage d'armature: Enrobage d'armature 1; Enrobage d'armature - Face inférieure: Paramètres de l'enrobage d'armature: Enrobage d'armature 1; Enrobage d'armature - Face supérieure: Paramètres de l'enrobage d'armature: Enrobage d'armature 1
Données d'identification - Nom du type: BG SI 1.90x 0.50 x 0.25 C25/30

# IfcSlab: Radier:BG 2.80 x 2.45 x 0.20, Radier:BG 2.80 x 2.45 x 0.20:434525
In: RdC
PredefinedType: BASESLAB; Material: BETON C25/30 0.2 m
Pset_SlabCommon - LoadBearing: yes; IsExternal: no; PitchAngle: 0 deg; Reference: BG 2.80 x 2.45 x 0.20
BaseQuantities - GrossArea: 6.86 m2; GrossVolume: 1.372 m3; Perimeter: 10.5 m; Width: 0.2 m
Autre - Catégorie: Fondations; Famille: Radier: BG 2.80 x 2.45 x 0.20; Famille et type: Radier: BG 2.80 x 2.45 x 0.20; ID du type: Radier: BG 2.80 x 2.45 x 0.20; Type: Radier: BG 2.80 x 2.45 x 0.20; Nom de la famille: Radier
Contraintes - Lié au volume: no; Niveau: Niveau: RdC; Décalage par rapport au niveau: -1.35 m
Cotes - Elévation à la base: -1.55 m; Elévation au niveau du noyau inférieur: -1.55 m; Elévation au niveau du noyau supérieur: -1.35 m; Elévation en haut: -1.35 m; Epaisseur: 0.2 m; Largeur: 2.8 m; Longueur: 2.45 m; Périmètre: 10.5 m; Surface: 6.86 m2; Volume: 1.372 m3
Phase de construction - Phase de création: Nouvelle construction
Structure - Activer le modèle analytique: yes; Enrobage d'armature - Autres faces: Paramètres de l'enrobage d'armature: Enrobage d'armature 1; Structure: yes; Enrobage d'armature - Face inférieure: Paramètres de l'enrobage d'armature: Enrobage d'armature 1; Enrobage d'armature - Face supérieure: Paramètres de l'enrobage d'armature: Enrobage d'armature 1
Construction - Epaisseur par défaut: 0.2 m
Données d'identification - Nom du type: BG 2.80 x 2.45 x 0.20
Graphismes - Couleur vue détail faible: 0
Matériaux et finitions - Matériau structurel: BETON C25/30
Propriétés analytiques - Rugosité: 3; Coefficient d'absorbance: 0.7

# IfcSlab: Sol:BG DALLAGE BA 0.13 C25/30, Sol:BG DALLAGE BA 0.13 C25/30:437144
In: RdC
PredefinedType: FLOOR; Material: AEC Béton, C25/30 0.13 m
Pset_SlabCommon - LoadBearing: yes; IsExternal: no; PitchAngle: 0 deg; Reference: BG DALLAGE BA 0.13 C25/30; ThermalTransmittance: 8.04615 kg/K/s3
BaseQuantities - GrossArea: 598.051 m2; GrossVolume: 77.7466 m3; Perimeter: 124.17 m; Width: 0.13 m
Autre - Catégorie: Sols; Famille: Sol: BG DALLAGE BA 0.13 C25/30; Famille et type: Sol: BG DALLAGE BA 0.13 C25/30; ID du type: Sol: BG DALLAGE BA 0.13 C25/30; Type: Sol: BG DALLAGE BA 0.13 C25/30; Nom de la famille: Sol
Contraintes - Lié au volume: no; Limite de pièce: yes; Décalage par rapport au niveau: 0 m; Niveau: Niveau: RdC
Cotes - Elévation à la base: -0.13 m; Elévation en haut: 0 m; Epaisseur: 0.13 m; Périmètre: 124.17 m; Surface: 598.051 m2; Volume: 77.7466 m3
Phase de construction - Phase de création: Nouvelle construction
Structure - Activer le modèle analytique: no; Structure: no
Construction - Fonction: Intérieur; Epaisseur par défaut: 0.13 m
Données d'identification - Nom du type: BG DALLAGE BA 0.13 C25/30
Graphismes - Couleur vue détail faible: 0
Matériaux et finitions - Matériau structurel: AEC Béton, C25/30
Propriétés analytiques - Rugosité: 3; Coefficient d'absorbance: 0.7; Coefficient de transfert de chaleur (U): 8.04615; Masse thermique: 196443; Résistance thermique (R): 0.124283

# IfcSlab: Sol:BG DALLE BA 0.18 C25/30 (4)
PredefinedType: FLOOR; Material: AEC Béton, C25/30 0.18 m
Pset_SlabCommon - LoadBearing: yes; IsExternal: no; Reference: BG DALLE BA 0.18 C25/30; ThermalTransmittance: 5.81111 kg/K/s3; PitchAngle: 0 deg
BaseQuantities - Width: 0.18 m
Autre - Catégorie: Sols; Famille: Sol: BG DALLE BA 0.18 C25/30; Famille et type: Sol: BG DALLE BA 0.18 C25/30; ID du type: Sol: BG DALLE BA 0.18 C25/30; Type: Sol: BG DALLE BA 0.18 C25/30; Nom de la famille: Sol
Contraintes - Lié au volume: no; Limite de pièce: yes
Cotes - Epaisseur: 0.18 m
Phase de construction - Phase de création: Nouvelle construction
Structure - Activer le modèle analytique: yes; Enrobage d'armature - Autres faces: Paramètres de l'enrobage d'armature: Enrobage d'armature 1; Structure: yes; Enrobage d'armature - Face inférieure: Paramètres de l'enrobage d'armature: Enrobage d'armature 1; Enrobage d'armature - Face supérieure: Paramètres de l'enrobage d'armature: Enrobage d'armature 1
Construction - Epaisseur par défaut: 0.18 m; Fonction: Intérieur
Données d'identification - Nom du type: BG DALLE BA 0.18 C25/30
Graphismes - Couleur vue détail faible: 0
Matériaux et finitions - Matériau structurel: AEC Béton, C25/30
Propriétés analytiques - Rugosité: 3; Coefficient d'absorbance: 0.7; Coefficient de transfert de chaleur (U): 5.81111; Masse thermique: 271998; Résistance thermique (R): 0.172084
Name (Sol:BG DALLE BA 0.18 C25/30:...) | In | GrossArea (m2) = Surface (m2) | GrossVolume (m3) = Volume (m3) | Perimeter (m) | Décalage par rapport au niveau (m) | Niveau | Elévation à la base (m) = Elévation au niveau du noyau inférieur (m) | Elévation au niveau du noyau supérieur (m) = Elévation en haut (m) | Périmètre (m)
425877 | Niveau 1 | 587.016 | 105.663 | 123.79 | 0 | Niveau: Niveau 1 | 3.34 | 3.52 | 120.5
427579 | RdC | 4.2 | 0.756 | 8.6 | 1.76 | Niveau: RdC | 1.58 | 1.76 | 8.6
443060 | Niveau 2 | 587.016 | 105.663 | 123.79 | 0 | Niveau: Niveau 2 | 6.86 | 7.04 | 120.5
443147 | Niveau 1 | 4.2 | 0.756 | 8.6 | 1.76 | Niveau: Niveau 1 | 5.1 | 5.28 | 8.6

# IfcSlab: Sol:BG DALLE BA 0.20 C25/30 (2)
In: Terrasse brut
PredefinedType: FLOOR; Material: AEC Béton, C25/30 0.2 m
Pset_SlabCommon - LoadBearing: yes; IsExternal: no; Reference: BG DALLE BA 0.20 C25/30; ThermalTransmittance: 5.23 kg/K/s3
Autre - Catégorie: Sols; Famille: Sol: BG DALLE BA 0.20 C25/30; Famille et type: Sol: BG DALLE BA 0.20 C25/30; ID du type: Sol: BG DALLE BA 0.20 C25/30; Type: Sol: BG DALLE BA 0.20 C25/30; Nom de la famille: Sol
Contraintes - Lié au volume: no; Limite de pièce: yes; Niveau: Niveau: Terrasse brut
Cotes - Epaisseur: 0.2 m
Phase de construction - Phase de création: Nouvelle construction
Structure - Activer le modèle analytique: yes; Enrobage d'armature - Autres faces: Paramètres de l'enrobage d'armature: Enrobage d'armature 1; Structure: yes; Enrobage d'armature - Face inférieure: Paramètres de l'enrobage d'armature: Enrobage d'armature 1; Enrobage d'armature - Face supérieure: Paramètres de l'enrobage d'armature: Enrobage d'armature 1
Construction - Fonction: Intérieur; Epaisseur par défaut: 0.2 m
Données d'identification - Nom du type: BG DALLE BA 0.20 C25/30
Graphismes - Couleur vue détail faible: 0
Matériaux et finitions - Matériau structurel: AEC Béton, C25/30
Propriétés analytiques - Rugosité: 3; Coefficient d'absorbance: 0.7; Coefficient de transfert de chaleur (U): 5.23; Masse thermique: 302220; Résistance thermique (R): 0.191205
Name (Sol:BG DALLE BA 0.20 C25/30:...) | GrossArea (m2) | Perimeter (m) = Périmètre (m) | Décalage par rapport au niveau (m) | Elévation à la base (m) = Elévation au niveau du noyau inférieur (m) | Elévation au niveau du noyau supérieur (m) = Elévation en haut (m) | Surface (m2) | Volume (m3)
451682 | 73.588 | 43.43 | 0 | 10.05 | 10.25 | 71.5276 | 14.3055
452998 | 3.41515 | 7.43 | 0.39 | 10.44 | 10.64 | 3.41515 | 0.68303 | Pset_SlabCommon - PitchAngle: 0 deg; BaseQuantities - GrossVolume: 0.68303 m3; Width: 0.2 m

# IfcWallStandardCase: Mur de base:BG VOILE BA 0.18 C25/30 (26)
Type - PredefinedType: STANDARD; Material: AEC Béton, C25/30 0.18 m
Type - Autre - Catégorie: Murs; Nom de la famille: Mur de base
Type - Construction - Fonction: Extérieur; Retournement aux extrémités: Aucun(e); Retournement aux insertions: Ne pas retourner; Largeur: 0.18 m
Type - Données d'identification - Nom du type: BG VOILE BA 0.18 C25/30
Type - Graphismes - Couleur vue détail faible: 0
Type - Matériaux et finitions - Matériau structurel: AEC Béton, C25/30
Type - Propriétés analytiques - Rugosité: 3; Coefficient d'absorbance: 0.7; Coefficient de transfert de chaleur (U): 5.81111; Masse thermique: 271998; Résistance thermique (R): 0.172084
BaseQuantities - Width: 0.18 m
Autre - Famille: Mur de base: BG VOILE BA 0.18 C25/30; Famille et type: Mur de base: BG VOILE BA 0.18 C25/30; ID du type: Mur de base: BG VOILE BA 0.18 C25/30; Type: Mur de base: BG VOILE BA 0.18 C25/30
Contraintes - Extension inférieure: 0 m; Extension supérieure: 0 m; Lié au volume: no; Ligne de justification: Axe du mur; Limite de pièce: yes; Partie inférieure attachée: no; Partie supérieure attachée: no
Phase de construction - Phase de création: Nouvelle construction
Structure - Activer le modèle analytique: yes; Enrobage d'armature - Autres faces: Paramètres de l'enrobage d'armature: Enrobage d'armature 1; Enrobage d'armature - Face extérieure: Paramètres de l'enrobage d'armature: Enrobage d'armature 1; Enrobage d'armature - Face intérieure: Paramètres de l'enrobage d'armature: Enrobage d'armature 1; Structure: yes; Utilisation structurelle: Porteur
Pset_WallCommon - LoadBearing: yes; ExtendToStructure: no; IsExternal: yes; Reference: BG VOILE BA 0.18 C25/30; ThermalTransmittance: 5.81111 kg/K/s3
Name (Mur de base:BG VOILE BA 0.18 C25/30:...) | In | Height (m) = Hauteur non contrainte (m) | Length (m) | GrossSideArea (m2) = Surface (m2) | GrossFootprintArea (m2) | GrossVolume (m3) = Volume (m3) | Contrainte supérieure | Décalage supérieur (m) | Contrainte inférieure | Décalage inférieur (m) | Longueur (m)
418702 | RdC | 4.87 | 2.405 | 11.7124 | 0.4329 | 2.10822 | Niveau: Niveau 1 | 0 | Niveau: RdC | -1.35 | 2.315
418899 | RdC | 4.87 | 1.67 | 8.1329 | 0.3006 | 1.46392 | Niveau: Niveau 1 | 0 | Niveau: RdC | -1.35 | 1.85
419226 | Fondations | 4.22 | 5.99 | 25.2778 | 1.0782 | 4.55 | Niveau: Niveau 1 | 0 | Niveau: Fondations | 0 | 5.99
419415 | Fondations | 4.22 | 3.07 | 12.9554 | 0.5526 | 2.33197 | Niveau: Niveau 1 | 0 | Niveau: Fondations | 0 | 3.16
419982 | RdC | 4.87 | 2.405 | 11.7124 | 0.4329 | 2.10822 | Niveau: Niveau 1 | 0 | Niveau: RdC | -1.35 | 2.315
439017 | Fondations | 4.22 | 2.98 | 12.5756 | 0.5364 | 2.26361 | Niveau: Niveau 1 | 0 | Niveau: Fondations | 0 | 2.98
439707 | Fondations | 4.22 | 2.035 | 8.5877 | 0.3663 | 1.54579 | Niveau: Niveau 1 | 0 | Niveau: Fondations | 0 | 2.035
440128 | RdC | 1.35 | 1.67 | 2.2545 | 0.3006 | 0.40581 | Niveau: RdC | 0 | Niveau: RdC | -1.35 | 1.85
442321 | Niveau 1 | 3.52 | 2.405 | 8.4656 | 0.4329 | 1.52381 | Niveau: Niveau 2 | 0 | Niveau: Niveau 1 | 0 | 2.315
442323 | Niveau 1 | 3.52 | 1.67 | 5.8784 | 0.3006 | 1.05811 | Niveau: Niveau 2 | 0 | Niveau: Niveau 1 | 0 | 1.85
442325 | Niveau 1 | 3.52 | 5.99 | 21.0848 | 1.0782 | 3.79526 | Niveau: Niveau 2 | 0 | Niveau: Niveau 1 | 0 | 5.99
442327 | Niveau 1 | 3.52 | 3.07 | 10.8064 | 0.5526 | 1.94515 | Niveau: Niveau 2 | 0 | Niveau: Niveau 1 | 0 | 3.16
442329 | Niveau 1 | 3.52 | 2.405 | 8.4656 | 0.4329 | 1.52381 | Niveau: Niveau 2 | 0 | Niveau: Niveau 1 | 0 | 2.315
442358 | Niveau 1 | 3.52 | 2.98 | 10.4896 | 0.5364 | 1.88813 | Niveau: Niveau 2 | 0 | Niveau: Niveau 1 | 0 | 2.98
442360 | Niveau 1 | 3.52 | 2.035 | 7.1632 | 0.3663 | 1.28938 | Niveau: Niveau 2 | 0 | Niveau: Niveau 1 | 0 | 2.035
446413 | Niveau 2 | 4.76 | 1.72 | 7.8112 | 0.3096 | 1.40602 | Niveau: Acrotere | 0 | Niveau: Niveau 2 | 0 | 1.72
446415 | Niveau 2 | 3.6 | 1.825 | 6.57 | 0.3285 | 1.1826 | Niveau: Terrasse brut | 0.39 | Niveau: Niveau 2 | 0 | 1.735
446417 | Niveau 2 | 4.76 | 1.76 | 8.0536 | 0.3168 | 1.44965 | Niveau: Acrotere | 0 | Niveau: Niveau 2 | 0 | 1.85
446419 | Niveau 2 | 4.76 | 5.99 | 28.5124 | 1.0782 | 5.13223 | Niveau: Acrotere | 0 | Niveau: Niveau 2 | 0 | 5.99
446421 | Niveau 2 | 4.76 | 3.07 | 14.6132 | 0.5526 | 2.63038 | Niveau: Acrotere | 0 | Niveau: Niveau 2 | 0 | 3.16
446423 | Niveau 2 | 3.6 | 2.405 | 8.3871 | 0.4329 | 1.50968 | Niveau: Terrasse brut | 0.39 | Niveau: Niveau 2 | 0 | 2.225
446429 | Niveau 2 | 4.76 | 3.07 | 14.2892 | 0.5364 | 2.57206 | Niveau: Acrotere | 0 | Niveau: Niveau 2 | 0 | 2.98
446431 | Niveau 2 | 3.01 | 2.125 | 6.39625 | 0.3825 | 1.15133 | Niveau: Terrasse brut | -0.2 | Niveau: Niveau 2 | 0 | 2.125
452380 | Terrasse brut | 1.75 | 3.11 | 5.4425 | 0.5598 | 0.97965 | Niveau: Acrotere | 0 | Niveau: Terrasse brut | -0.2 | 3.11
452904 | Terrasse brut | 0.59 | 1.67 | 0.9853 | 0.3006 | 0.177354 | Niveau: Terrasse brut | 0.39 | Niveau: Terrasse brut | -0.2 | 1.85
453348 | Niveau 2 | 4.76 | 0.58 | 2.7608 | 0.1044 | 0.496944 | Niveau: Acrotere | 0 | Niveau: Niveau 2 | 0 | 0.49

# IfcWallStandardCase: Mur de base:BG VOILE BA 0.20 C25/30 (40)
Type - PredefinedType: STANDARD; Material: AEC Béton, C25/30 0.2 m
Type - Autre - Catégorie: Murs; Nom de la famille: Mur de base
Type - Construction - Fonction: Extérieur; Largeur: 0.2 m; Retournement aux extrémités: Aucun(e); Retournement aux insertions: Ne pas retourner
Type - Données d'identification - Nom du type: BG VOILE BA 0.20 C25/30
Type - Graphismes - Couleur vue détail faible: 0
Type - Matériaux et finitions - Matériau structurel: AEC Béton, C25/30
Type - Propriétés analytiques - Coefficient d'absorbance: 0.7; Coefficient de transfert de chaleur (U): 5.23; Masse thermique: 302220; Résistance thermique (R): 0.191205; Rugosité: 3
BaseQuantities - Width: 0.2 m
Autre - Famille: Mur de base: BG VOILE BA 0.20 C25/30; Famille et type: Mur de base: BG VOILE BA 0.20 C25/30; ID du type: Mur de base: BG VOILE BA 0.20 C25/30; Type: Mur de base: BG VOILE BA 0.20 C25/30
Contraintes - Extension inférieure: 0 m; Extension supérieure: 0 m; Lié au volume: no; Ligne de justification: Axe du mur; Limite de pièce: yes; Partie inférieure attachée: no; Partie supérieure attachée: no
Phase de construction - Phase de création: Nouvelle construction
Pset_WallCommon - Reference: BG VOILE BA 0.20 C25/30; ExtendToStructure: no; IsExternal: yes; ThermalTransmittance: 5.23 kg/K/s3
Name (Mur de base:BG VOILE BA 0.20 C25/30:...) | In | Height (m) = Hauteur non contrainte (m) | Length (m) | GrossSideArea (m2) = Surface (m2) | GrossFootprintArea (m2) | GrossVolume (m3) = Volume (m3) | Contrainte inférieure | Contrainte supérieure | Décalage inférieur (m) | Décalage supérieur (m) | Longueur (m) | Activer le modèle analytique = Structure = LoadBearing | Enrobage d'armature - Autres faces = Enrobage d'armature - Face extérieure = Enrobage d'armature - Face intérieure | Utilisation structurelle
410724 | Fondations | 4.22 | 39.12 | 138.038 | 7.824 | 27.6077 | Niveau: Fondations | Niveau: Niveau 1 | 0 | 0 | 38.92 | yes | Paramètres de l'enrobage d'armature: Enrobage d'armature 1 | Porteur
416850 | Fondations | 4.22 | 2.5 | 10.55 | 0.5 | 2.11 | Niveau: Fondations | Niveau: Niveau 1 | 0 | 0 | 2.7 | yes | Paramètres de l'enrobage d'armature: Enrobage d'armature 1 | Porteur
416852 | Fondations | 4.22 | 5.85 | 24.687 | 1.17 | 4.9374 | Niveau: Fondations | Niveau: Niveau 1 | 0 | 0 | 5.94 | yes | Paramètres de l'enrobage d'armature: Enrobage d'armature 1 | Porteur
416854 | Fondations | 4.22 | 16.46 | 57.49 | 3.292 | 11.498 | Niveau: Fondations | Niveau: Niveau 1 | 0 | 0 | 16.66 | yes | Paramètres de l'enrobage d'armature: Enrobage d'armature 1 | Porteur
416856 | Fondations | 4.22 | 3 | 12.66 | 0.6 | 2.532 | Niveau: Fondations | Niveau: Niveau 1 | 0 | 0 | 3 | yes | Paramètres de l'enrobage d'armature: Enrobage d'armature 1 | Porteur
417377 | Fondations | 4.22 | 14.8 | 57.524 | 2.96 | 11.5048 | Niveau: Fondations | Niveau: Niveau 1 | 0 | 0 | 14.8 | yes | Paramètres de l'enrobage d'armature: Enrobage d'armature 1 | Porteur
417552 | Fondations | 4.22 | 16.46 | 57.8692 | 3.292 | 11.5738 | Niveau: Fondations | Niveau: Niveau 1 | 0 | 0 | 16.66 | yes | Paramètres de l'enrobage d'armature: Enrobage d'armature 1 | Porteur
417795 | Fondations | 4.22 | 4.5 | 18.99 | 0.9 | 3.798 | Niveau: Fondations | Niveau: Niveau 1 | 0 | 0 | 4.5 | yes | Paramètres de l'enrobage d'armature: Enrobage d'armature 1 | Porteur
418211 | Fondations | 4.22 | 14.8 | 57.524 | 2.96 | 11.5048 | Niveau: Fondations | Niveau: Niveau 1 | 0 | 0 | 14.8 | yes | Paramètres de l'enrobage d'armature: Enrobage d'armature 1 | Porteur
424964 | Fondations | 4.22 | 2.4 | 10.128 | 0.48 | 2.0256 | Niveau: Fondations | Niveau: Niveau 1 | 0 | 0 | 2.4 | yes | Paramètres de l'enrobage d'armature: Enrobage d'armature 1 | Porteur
425740 | Fondations | 4.22 | 2.4 | 10.128 | 0.48 | 2.0256 | Niveau: Fondations | Niveau: Niveau 1 | 0 | 0 | 2.4 | yes | Paramètres de l'enrobage d'armature: Enrobage d'armature 1 | Porteur
442282 | Niveau 1 | 3.52 | 39.12 | 110.912 | 7.824 | 22.1824 | Niveau: Niveau 1 | Niveau: Niveau 2 | 0 | 0 | 38.92 | yes | Paramètres de l'enrobage d'armature: Enrobage d'armature 1 | Porteur
442307 | Niveau 1 | 3.52 | 5.85 | 20.592 | 1.17 | 4.1184 | Niveau: Niveau 1 | Niveau: Niveau 2 | 0 | 0 | 5.94 | yes | Paramètres de l'enrobage d'armature: Enrobage d'armature 1 | Porteur
442309 | Niveau 1 | 3.52 | 16.46 | 46.4576 | 3.292 | 9.29152 | Niveau: Niveau 1 | Niveau: Niveau 2 | 0 | 0 | 16.66 | yes | Paramètres de l'enrobage d'armature: Enrobage d'armature 1 | Porteur
442313 | Niveau 1 | 3.52 | 14.8 | 47.578 | 2.96 | 9.5156 | Niveau: Niveau 1 | Niveau: Niveau 2 | 0 | 0 | 14.8 | yes | Paramètres de l'enrobage d'armature: Enrobage d'armature 1 | Porteur
442315 | Niveau 1 | 3.52 | 16.46 | 46.4576 | 3.292 | 9.29152 | Niveau: Niveau 1 | Niveau: Niveau 2 | 0 | 0 | 16.66 | yes | Paramètres de l'enrobage d'armature: Enrobage d'armature 1 | Porteur
442317 | Niveau 1 | 3.52 | 4.5 | 15.84 | 0.9 | 3.168 | Niveau: Niveau 1 | Niveau: Niveau 2 | 0 | 0 | 4.5 | yes | Paramètres de l'enrobage d'armature: Enrobage d'armature 1 | Porteur
442319 | Niveau 1 | 3.52 | 14.8 | 47.578 | 2.96 | 9.5156 | Niveau: Niveau 1 | Niveau: Niveau 2 | 0 | 0 | 14.8 | yes | Paramètres de l'enrobage d'armature: Enrobage d'armature 1 | Porteur
442354 | Niveau 1 | 3.52 | 2.4 | 8.448 | 0.48 | 1.6896 | Niveau: Niveau 1 | Niveau: Niveau 2 | 0 | 0 | 2.4 | yes | Paramètres de l'enrobage d'armature: Enrobage d'armature 1 | Porteur
442356 | Niveau 1 | 3.52 | 2.4 | 8.448 | 0.48 | 1.6896 | Niveau: Niveau 1 | Niveau: Niveau 2 | 0 | 0 | 2.4 | yes | Paramètres de l'enrobage d'armature: Enrobage d'armature 1 | Porteur
444667 | Niveau 2 | 0.89 | 39.12 | 34.8168 | 7.824 | 6.96336 | Niveau: Niveau 2 |  | 0 | 0 | 38.92 | yes | Paramètres de l'enrobage d'armature: Enrobage d'armature 1 | Porteur
445266 | Niveau 2 | 0.89 | 16.67 | 14.8363 | 3.334 | 2.96726 | Niveau: Niveau 2 |  | 0 | 0 | 16.66 | yes | Paramètres de l'enrobage d'armature: Enrobage d'armature 1 | Porteur
445590 | Niveau 2 | 0.89 | 16.6595 | 14.8269 | 3.3319 | 2.96539 | Niveau: Niveau 2 |  | 0 | 0 | 16.6595 | yes | Paramètres de l'enrobage d'armature: Enrobage d'armature 1 | Porteur
446411 | Niveau 2 | 4.76 | 5.85 | 27.846 | 1.17 | 5.5692 | Niveau: Niveau 2 | Niveau: Acrotere | 0 | 0 | 5.94 | yes | Paramètres de l'enrobage d'armature: Enrobage d'armature 1 | Porteur
446425 | Niveau 2 | 4.76 | 2.42 | 11.5192 | 0.484 | 2.30384 | Niveau: Niveau 2 | Niveau: Acrotere | 0 | 0 | 2.32 | yes | Paramètres de l'enrobage d'armature: Enrobage d'armature 1 | Porteur
446427 | Niveau 2 | 4.76 | 2.4 | 11.424 | 0.48 | 2.2848 | Niveau: Niveau 2 | Niveau: Acrotere | 0 | 0 | 2.3 | yes | Paramètres de l'enrobage d'armature: Enrobage d'armature 1 | Porteur
447258 | Niveau 2 | 3.76 | 39.12 | 120.043 | 7.824 | 24.0086 | Niveau: Niveau 2 | Niveau: Terrasse brut | 0.21 | 0.76 | 38.9205 | yes | Paramètres de l'enrobage d'armature: Enrobage d'armature 1 | Porteur
448679 | Niveau 2 | 3.21 | 12.06 | 38.3916 | 2.392 | 7.67832 | Niveau: Niveau 2 | Niveau: Terrasse brut | 0 | 0 | 11.96 | no |  | Non porteur
448893 | Niveau 2 | 3.97 | 12.06 | 45.1712 | 2.392 | 9.03424 | Niveau: Niveau 2 | Niveau: Terrasse brut | 0 | 0.76 | 11.96 | yes | Paramètres de l'enrobage d'armature: Enrobage d'armature 1 | Porteur
449741 | Niveau 2 | 3.97 | 12.06 | 45.1712 | 2.392 | 9.03424 | Niveau: Niveau 2 | Niveau: Terrasse brut | 0 | 0.76 | 11.96 | yes | Paramètres de l'enrobage d'armature: Enrobage d'armature 1 | Porteur
449856 | Niveau 2 | 3.76 | 16.46 | 50.2976 | 3.292 | 10.0595 | Niveau: Niveau 2 | Niveau: Terrasse brut | 0.21 | 0.76 | 16.66 | yes | Paramètres de l'enrobage d'armature: Enrobage d'armature 1 | Porteur
450434 | Niveau 2 | 3.76 | 16.46 | 50.2976 | 3.292 | 10.0595 | Niveau: Niveau 2 | Niveau: Terrasse brut | 0.21 | 0.76 | 16.66 | yes | Paramètres de l'enrobage d'armature: Enrobage d'armature 1 | Porteur
450856 | Niveau 2 | 0.89 | 1.27 | 1.0623 | 0.254 | 0.21246 | Niveau: Niveau 2 |  | 0 | 0 | 1.37 | yes | Paramètres de l'enrobage d'armature: Enrobage d'armature 1 | Porteur
450948 | Niveau 2 | 0.89 | 1.27 | 1.0623 | 0.254 | 0.21246 | Niveau: Niveau 2 |  | 0 | 0 | 1.37 | yes | Paramètres de l'enrobage d'armature: Enrobage d'armature 1 | Porteur
451028 | Niveau 2 | 0.89 | 1.37 | 1.1513 | 0.274 | 0.23026 | Niveau: Niveau 2 |  | 0 | 0 | 1.47 | yes | Paramètres de l'enrobage d'armature: Enrobage d'armature 1 | Porteur
451140 | Niveau 2 | 0.89 | 1.37 | 1.1513 | 0.274 | 0.23026 | Niveau: Niveau 2 |  | 0 | 0 | 1.47 | yes | Paramètres de l'enrobage d'armature: Enrobage d'armature 1 | Porteur
451404 | Terrasse brut | 1.75 | 5.4 | 9.45 | 1.08 | 1.89 | Niveau: Terrasse brut | Niveau: Acrotere | -0.2 | 0 | 5.6 | yes | Paramètres de l'enrobage d'armature: Enrobage d'armature 1 | Porteur
452260 | Terrasse brut | 1.75 | 1.2 | 2.1 | 0.24 | 0.42 | Niveau: Terrasse brut | Niveau: Acrotere | -0.2 | 0 | 1.2 | yes | Paramètres de l'enrobage d'armature: Enrobage d'armature 1 | Porteur
452324 | Terrasse brut | 1.75 | 1.2 | 2.1 | 0.24 | 0.42 | Niveau: Terrasse brut | Niveau: Acrotere | -0.2 | 0 | 1.2 | yes | Paramètres de l'enrobage d'armature: Enrobage d'armature 1 | Porteur
452513 | Niveau 2 | 4.76 | 2.86 | 13.5136 | 0.552 | 2.70272 | Niveau: Niveau 2 | Niveau: Acrotere | 0 | 0 | 2.76 | yes | Paramètres de l'enrobage d'armature: Enrobage d'armature 1 | Porteur
